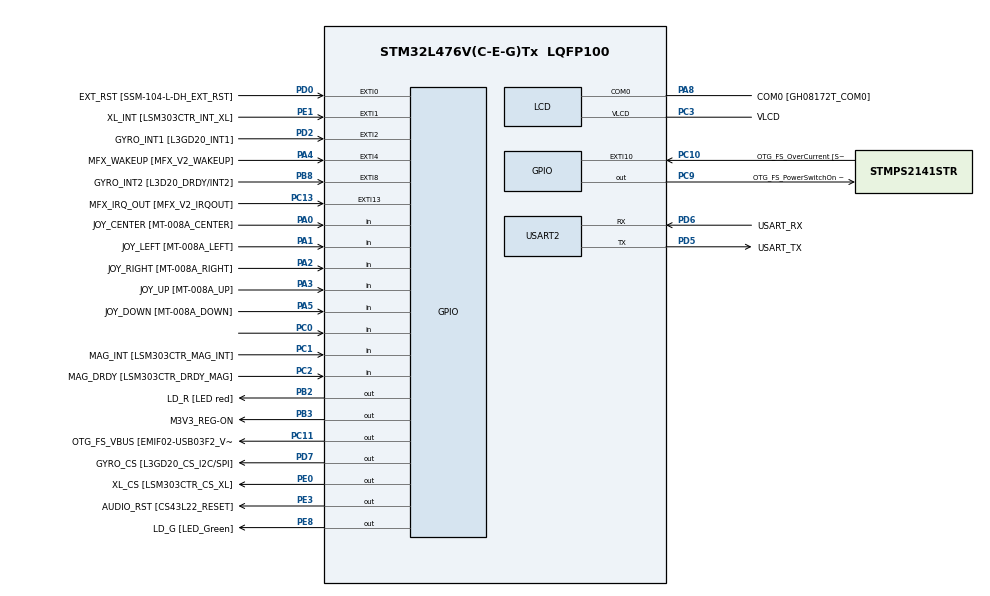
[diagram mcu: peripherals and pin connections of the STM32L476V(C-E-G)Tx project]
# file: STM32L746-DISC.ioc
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FREERTOS.Tasks01=defaultTask,0,128,StartDefaultTask,Default,NULL
Mcu.Family=STM32L4
Mcu.Name=STM32L476V(C-E-G)Tx
Mcu.Package=LQFP100
NVIC.PriorityGroup=NVIC_PRIORITYGROUP_4
PA0.GPIO_Label=JOY_CENTER [MT-008A_CENTER]
PA0.GPIO_Mode=GPIO_MODE_INPUT
PA0.GPIO_PuPd=GPIO_PULLDOWN
PA0.Signal=GPIO_Input
PA1.GPIO_Label=JOY_LEFT [MT-008A_LEFT]
PA1.GPIO_Mode=GPIO_MODE_INPUT
PA1.GPIO_PuPd=GPIO_PULLDOWN
PA1.Signal=GPIO_Input
PA10.GPIO_Label=COM2 [GH08172T_COM2]
PA10.GPIO_Mode=GPIO_MODE_AF_PP
PA10.GPIO_PuPd=GPIO_NOPULL
PA10.GPIO_Speed=GPIO_SPEED_FREQ_LOW
PA10.Signal=LCD_COM2
PA11.GPIO_Label=OTG_FS_DM [EMIF02-USB03F2_D-out]
PA11.GPIO_Mode=GPIO_MODE_AF_PP
PA11.GPIO_PuPd=GPIO_NOPULL
PA11.GPIO_Speed=GPIO_SPEED_FREQ_VERY_HIGH
PA11.Signal=USB_OTG_FS_DM
PA12.GPIO_Label=OTG_FS_DP [EMIF02-USB03F2_D+out]
PA12.GPIO_Mode=GPIO_MODE_AF_PP
PA12.GPIO_PuPd=GPIO_NOPULL
PA12.GPIO_Speed=GPIO_SPEED_FREQ_VERY_HIGH
PA12.Signal=USB_OTG_FS_DP
PA13\ (JTMS-SWDIO).GPIO_Label=SWDIO
PA13\ (JTMS-SWDIO).Signal=SYS_JTMS-SWDIO
PA14\ (JTCK-SWCLK).GPIO_Label=SWCLK
PA14\ (JTCK-SWCLK).Signal=SYS_JTCK-SWCLK
PA15\ (JTDI).GPIO_Label=SEG10 [GH08172T_SEG10]
PA15\ (JTDI).GPIO_Mode=GPIO_MODE_AF_PP
PA15\ (JTDI).GPIO_PuPd=GPIO_NOPULL
PA15\ (JTDI).GPIO_Speed=GPIO_SPEED_FREQ_LOW
PA15\ (JTDI).Signal=LCD_SEG17
PA2.GPIO_Label=JOY_RIGHT [MT-008A_RIGHT]
PA2.GPIO_Mode=GPIO_MODE_INPUT
PA2.GPIO_PuPd=GPIO_PULLDOWN
PA2.Signal=GPIO_Input
PA3.GPIO_Label=JOY_UP [MT-008A_UP]
PA3.GPIO_Mode=GPIO_MODE_INPUT
PA3.GPIO_PuPd=GPIO_PULLDOWN
PA3.Signal=GPIO_Input
PA4.GPIO_Label=MFX_WAKEUP [MFX_V2_WAKEUP]
PA4.GPIO_ModeDefaultEXTI=GPIO_MODE_EVT_RISING
PA4.GPIO_PuPd=GPIO_NOPULL
PA4.Signal=GPXTI4
PA5.GPIO_Label=JOY_DOWN [MT-008A_DOWN]
PA5.GPIO_Mode=GPIO_MODE_INPUT
PA5.GPIO_PuPd=GPIO_PULLDOWN
PA5.Signal=GPIO_Input
PA6.GPIO_Label=SEG23 [GH08172T_SEG23]
PA6.GPIO_Mode=GPIO_MODE_AF_PP
PA6.GPIO_PuPd=GPIO_NOPULL
PA6.GPIO_Speed=GPIO_SPEED_FREQ_LOW
PA6.Signal=LCD_SEG3
PA7.GPIO_Label=SEG0 [GH08172T_SEG0]
PA7.GPIO_Mode=GPIO_MODE_AF_PP
PA7.GPIO_PuPd=GPIO_NOPULL
PA7.GPIO_Speed=GPIO_SPEED_FREQ_LOW
PA7.Signal=LCD_SEG4
PA8.GPIO_Label=COM0 [GH08172T_COM0]
PA8.GPIO_Mode=GPIO_MODE_AF_PP
PA8.GPIO_PuPd=GPIO_NOPULL
PA8.GPIO_Speed=GPIO_SPEED_FREQ_LOW
PA8.Mode=Static
PA8.Signal=LCD_COM0
PA9.GPIO_Label=COM1 [GH08172T_COM1]
PA9.GPIO_Mode=GPIO_MODE_AF_PP
PA9.GPIO_PuPd=GPIO_NOPULL
PA9.GPIO_Speed=GPIO_SPEED_FREQ_LOW
PA9.Signal=LCD_COM1
PB0.GPIO_Label=SEG21 [GH08172T_SEG21]
PB0.GPIO_Mode=GPIO_MODE_AF_PP
PB0.GPIO_PuPd=GPIO_NOPULL
PB0.GPIO_Speed=GPIO_SPEED_FREQ_LOW
PB0.Signal=LCD_SEG5
PB1.GPIO_Label=SEG2 [GH08172T_SEG2]
PB1.GPIO_Mode=GPIO_MODE_AF_PP
PB1.GPIO_PuPd=GPIO_NOPULL
PB1.GPIO_Speed=GPIO_SPEED_FREQ_LOW
PB1.Signal=LCD_SEG6
PB10.GPIO_Label=MFX_I2C_SLC [MFX_V2_I2C_SCL]
PB10.GPIO_Mode=GPIO_MODE_AF_OD
PB10.GPIO_PuPdOD=GPIO_PULLUP
PB10.GPIO_Speed=GPIO_SPEED_FREQ_VERY_HIGH
PB10.Signal=I2C2_SCL
PB11.GPIO_Label=MFX_I2C_SDA [MFX_V2_I2C_SDA]
PB11.GPIO_Mode=GPIO_MODE_AF_OD
PB11.GPIO_PuPdOD=GPIO_PULLUP
PB11.GPIO_Speed=GPIO_SPEED_FREQ_VERY_HIGH
PB11.Signal=I2C2_SDA
PB12.GPIO_Label=SEG20 [GH08172T_SEG20]
PB12.GPIO_Mode=GPIO_MODE_AF_PP
PB12.GPIO_PuPd=GPIO_NOPULL
PB12.GPIO_Speed=GPIO_SPEED_FREQ_LOW
PB12.Signal=LCD_SEG12
PB13.GPIO_Label=SEG3 [GH08172T_SEG3]
PB13.GPIO_Mode=GPIO_MODE_AF_PP
PB13.GPIO_PuPd=GPIO_NOPULL
PB13.GPIO_Speed=GPIO_SPEED_FREQ_LOW
PB13.Signal=LCD_SEG13
PB14.GPIO_Label=SEG19 [GH08172T_SEG19]
PB14.GPIO_Mode=GPIO_MODE_AF_PP
PB14.GPIO_PuPd=GPIO_NOPULL
PB14.GPIO_Speed=GPIO_SPEED_FREQ_LOW
PB14.Signal=LCD_SEG14
PB15.GPIO_Label=SEG4 [GH08172T_SEG4]
PB15.GPIO_Mode=GPIO_MODE_AF_PP
PB15.GPIO_PuPd=GPIO_NOPULL
PB15.GPIO_Speed=GPIO_SPEED_FREQ_LOW
PB15.Signal=LCD_SEG15
PB2.GPIO_Label=LD_R [LED red]
PB2.GPIO_ModeDefaultOutputPP=GPIO_MODE_OUTPUT_PP
PB2.GPIO_PuPd=GPIO_PULLUP
PB2.GPIO_Speed=GPIO_SPEED_FREQ_VERY_HIGH
PB2.Signal=GPIO_Output
PB3\ (JTDO-TRACESWO).GPIO_Label=M3V3_REG-ON
PB3\ (JTDO-TRACESWO).GPIO_ModeDefaultOutputPP=GPIO_MODE_OUTPUT_PP
PB3\ (JTDO-TRACESWO).GPIO_PuPd=GPIO_NOPULL
PB3\ (JTDO-TRACESWO).GPIO_Speed=GPIO_SPEED_FREQ_LOW
PB3\ (JTDO-TRACESWO).Signal=GPIO_Output
PB4\ (NJTRST).GPIO_Label=SEG11 [GH08172T_SEG11]
PB4\ (NJTRST).GPIO_Mode=GPIO_MODE_AF_PP
PB4\ (NJTRST).GPIO_PuPd=GPIO_NOPULL
PB4\ (NJTRST).GPIO_Speed=GPIO_SPEED_FREQ_LOW
PB4\ (NJTRST).Signal=LCD_SEG8
PB5.GPIO_Label=SEG12 [GH08172T_SEG12]
PB5.GPIO_Mode=GPIO_MODE_AF_PP
PB5.GPIO_PuPd=GPIO_NOPULL
PB5.GPIO_Speed=GPIO_SPEED_FREQ_LOW
PB5.Signal=LCD_SEG9
PB6.GPIO_FM6=__NULL
PB6.GPIO_Label=I2C1_SCL [SSM-104-L-DH_SCL]
PB6.GPIO_Mode=GPIO_MODE_AF_OD
PB6.GPIO_PuPdOD=GPIO_PULLUP
PB6.GPIO_Speed=GPIO_SPEED_FREQ_VERY_HIGH
PB6.Signal=I2C1_SCL
PB7.GPIO_FM7=__NULL
PB7.GPIO_Label=I2C1_SDA [SSM-104-L-DH_SDA]
PB7.GPIO_Mode=GPIO_MODE_AF_OD
PB7.GPIO_PuPdOD=GPIO_PULLUP
PB7.GPIO_Speed=GPIO_SPEED_FREQ_VERY_HIGH
PB7.Signal=I2C1_SDA
PB8.GPIO_Label=GYRO_INT2 [L3D20_DRDY/INT2]
PB8.GPIO_ModeDefaultEXTI=GPIO_MODE_EVT_RISING
PB8.GPIO_PuPd=GPIO_NOPULL
PB8.Signal=GPXTI8
PB9.GPIO_FM9=__NULL
PB9.GPIO_Label=COM3 [GH08172T_COM3]
PB9.GPIO_Mode=GPIO_MODE_AF_PP
PB9.GPIO_PuPd=GPIO_NOPULL
PB9.GPIO_Speed=GPIO_SPEED_FREQ_LOW
PB9.Signal=LCD_COM3
PC0.Signal=GPIO_Input
PC1.GPIO_Label=MAG_INT [LSM303CTR_MAG_INT]
PC1.GPIO_Mode=GPIO_MODE_INPUT
PC1.GPIO_PuPd=GPIO_NOPULL
PC1.Signal=GPIO_Input
PC10.GPIO_Label=OTG_FS_OverCurrent [STMPS2141STR_FAULT]
PC10.GPIO_ModeDefaultEXTI=GPIO_MODE_EVT_RISING
PC10.GPIO_PuPd=GPIO_NOPULL
PC10.Signal=GPXTI10
PC11.GPIO_Label=OTG_FS_VBUS [EMIF02-USB03F2_Vbus]
PC11.GPIO_ModeDefaultOutputPP=GPIO_MODE_OUTPUT_PP
PC11.GPIO_PuPd=GPIO_NOPULL
PC11.GPIO_Speed=GPIO_SPEED_FREQ_LOW
PC11.Signal=GPIO_Output
PC13.GPIO_Label=MFX_IRQ_OUT [MFX_V2_IRQOUT]
PC13.GPIO_ModeDefaultEXTI=GPIO_MODE_EVT_RISING
PC13.GPIO_PuPd=GPIO_NOPULL
PC13.Signal=GPXTI13
PC14-OSC32_IN\ (PC14).Signal=RCC_OSC32_IN
PC15-OSC32_OUT\ (PC15).Signal=RCC_OSC32_OUT
PC2.GPIO_Label=MAG_DRDY [LSM303CTR_DRDY_MAG]
PC2.GPIO_Mode=GPIO_MODE_INPUT
PC2.GPIO_PuPd=GPIO_NOPULL
PC2.Signal=GPIO_Input
PC3.GPIO_Label=VLCD
PC3.GPIO_Mode=GPIO_MODE_AF_PP
PC3.GPIO_PuPd=GPIO_NOPULL
PC3.GPIO_Speed=GPIO_SPEED_FREQ_LOW
PC3.Mode=Static
PC3.Signal=LCD_VLCD
PC4.GPIO_Label=SEG22 [GH08172T_SEG22]
PC4.GPIO_Mode=GPIO_MODE_AF_PP
PC4.GPIO_PuPd=GPIO_NOPULL
PC4.GPIO_Speed=GPIO_SPEED_FREQ_LOW
PC4.Signal=LCD_SEG22
PC5.GPIO_Label=SEG1 [GH08172T_SEG1]
PC5.GPIO_Mode=GPIO_MODE_AF_PP
PC5.GPIO_PuPd=GPIO_NOPULL
PC5.GPIO_Speed=GPIO_SPEED_FREQ_LOW
PC5.Signal=LCD_SEG23
PC6.GPIO_Label=SEG14 [GH08172T_SEG14]
PC6.GPIO_Mode=GPIO_MODE_AF_PP
PC6.GPIO_PuPd=GPIO_NOPULL
PC6.GPIO_Speed=GPIO_SPEED_FREQ_LOW
PC6.Signal=LCD_SEG24
PC7.GPIO_Label=SEG9 [GH08172T_SEG9]
PC7.GPIO_Mode=GPIO_MODE_AF_PP
PC7.GPIO_PuPd=GPIO_NOPULL
PC7.GPIO_Speed=GPIO_SPEED_FREQ_LOW
PC7.Signal=LCD_SEG25
PC8.GPIO_Label=SEG13 [GH08172T_SEG13]
PC8.GPIO_Mode=GPIO_MODE_AF_PP
PC8.GPIO_PuPd=GPIO_NOPULL
PC8.GPIO_Speed=GPIO_SPEED_FREQ_LOW
PC8.Signal=LCD_SEG26
PC9.GPIO_Label=OTG_FS_PowerSwitchOn [STMPS2141STR_EN]
PC9.GPIO_ModeDefaultOutputPP=GPIO_MODE_OUTPUT_PP
PC9.GPIO_PuPd=GPIO_NOPULL
PC9.GPIO_Speed=GPIO_SPEED_FREQ_LOW
PC9.PinState=GPIO_PIN_SET
PC9.Signal=GPIO_Output
PD0.GPIO_Label=EXT_RST [SSM-104-L-DH_EXT_RST]
PD0.GPIO_ModeDefaultEXTI=GPIO_MODE_EVT_RISING
PD0.GPIO_PuPd=GPIO_NOPULL
PD0.Signal=GPXTI0
PD1.GPIO_Label=MEMS_SCK [L3GD20_SCL/SPC]
PD1.GPIO_Mode=GPIO_MODE_AF_PP
PD1.GPIO_PuPd=GPIO_NOPULL
PD1.GPIO_Speed=GPIO_SPEED_FREQ_VERY_HIGH
PD1.Signal=SPI2_SCK
PD10.GPIO_Label=SEG17 [GH08172T_SEG17]
PD10.GPIO_Mode=GPIO_MODE_AF_PP
PD10.GPIO_PuPd=GPIO_NOPULL
PD10.GPIO_Speed=GPIO_SPEED_FREQ_LOW
PD10.Signal=LCD_SEG30
PD11.GPIO_Label=SEG6 [GH08172T_SEG6]
PD11.GPIO_Mode=GPIO_MODE_AF_PP
PD11.GPIO_PuPd=GPIO_NOPULL
PD11.GPIO_Speed=GPIO_SPEED_FREQ_LOW
PD11.Signal=LCD_SEG31
PD12.GPIO_Label=SEG16 [GH08172T_SEG16]
PD12.GPIO_Mode=GPIO_MODE_AF_PP
PD12.GPIO_PuPd=GPIO_NOPULL
PD12.GPIO_Speed=GPIO_SPEED_FREQ_LOW
PD12.Signal=LCD_SEG32
PD13.GPIO_Label=SEG7 [GH08172T_SEG7]
PD13.GPIO_Mode=GPIO_MODE_AF_PP
PD13.GPIO_PuPd=GPIO_NOPULL
PD13.GPIO_Speed=GPIO_SPEED_FREQ_LOW
PD13.Signal=LCD_SEG33
PD14.GPIO_Label=SEG15 [GH08172T_SEG15]
PD14.GPIO_Mode=GPIO_MODE_AF_PP
PD14.GPIO_PuPd=GPIO_NOPULL
PD14.GPIO_Speed=GPIO_SPEED_FREQ_LOW
PD14.Signal=LCD_SEG34
PD15.GPIO_Label=SEG8 [GH08172T_SEG8]
PD15.GPIO_Mode=GPIO_MODE_AF_PP
PD15.GPIO_PuPd=GPIO_NOPULL
PD15.GPIO_Speed=GPIO_SPEED_FREQ_LOW
PD15.Signal=LCD_SEG35
PD2.GPIO_Label=GYRO_INT1 [L3GD20_INT1]
PD2.GPIO_ModeDefaultEXTI=GPIO_MODE_EVT_RISING
PD2.GPIO_PuPd=GPIO_NOPULL
PD2.Signal=GPXTI2
PD3.GPIO_Label=MEMS_MISO [L3GD20_SA0/SDO]
PD3.GPIO_Mode=GPIO_MODE_AF_PP
PD3.GPIO_PuPd=GPIO_NOPULL
PD3.GPIO_Speed=GPIO_SPEED_FREQ_VERY_HIGH
PD3.Signal=SPI2_MISO
PD4.GPIO_Label=MEMS_MOSI [L3GD20_SDA/SDI/SDO]
PD4.GPIO_Mode=GPIO_MODE_AF_PP
PD4.GPIO_PuPd=GPIO_NOPULL
PD4.GPIO_Speed=GPIO_SPEED_FREQ_VERY_HIGH
PD4.Signal=SPI2_MOSI
PD5.GPIO_Label=USART_TX
PD5.GPIO_Mode=GPIO_MODE_AF_PP
PD5.GPIO_PuPd=GPIO_PULLUP
PD5.GPIO_Speed=GPIO_SPEED_FREQ_VERY_HIGH
PD5.Mode=Asynchronous
PD5.Signal=USART2_TX
PD6.GPIO_Label=USART_RX
PD6.GPIO_Mode=GPIO_MODE_AF_PP
PD6.GPIO_PuPd=GPIO_PULLUP
PD6.GPIO_Speed=GPIO_SPEED_FREQ_VERY_HIGH
PD6.Mode=Asynchronous
PD6.Signal=USART2_RX
PD7.GPIO_Label=GYRO_CS [L3GD20_CS_I2C/SPI]
PD7.GPIO_ModeDefaultOutputPP=GPIO_MODE_OUTPUT_PP
PD7.GPIO_PuPd=GPIO_NOPULL
PD7.GPIO_Speed=GPIO_SPEED_FREQ_VERY_HIGH
PD7.Signal=GPIO_Output
PD8.GPIO_Label=SEG18 [GH08172T_SEG18]
PD8.GPIO_Mode=GPIO_MODE_AF_PP
PD8.GPIO_PuPd=GPIO_NOPULL
PD8.GPIO_Speed=GPIO_SPEED_FREQ_LOW
PD8.Signal=LCD_SEG28
PD9.GPIO_Label=SEG5 [GH08172T_SEG5]
PD9.GPIO_Mode=GPIO_MODE_AF_PP
PD9.GPIO_PuPd=GPIO_NOPULL
PD9.GPIO_Speed=GPIO_SPEED_FREQ_LOW
PD9.Signal=LCD_SEG29
PE0.GPIO_Label=XL_CS [LSM303CTR_CS_XL]
PE0.GPIO_ModeDefaultOutputPP=GPIO_MODE_OUTPUT_PP
PE0.GPIO_PuPd=GPIO_NOPULL
PE0.GPIO_Speed=GPIO_SPEED_FREQ_LOW
PE0.Signal=GPIO_Output
PE1.GPIO_Label=XL_INT [LSM303CTR_INT_XL]
PE1.GPIO_ModeDefaultEXTI=GPIO_MODE_EVT_RISING
PE1.GPIO_PuPd=GPIO_NOPULL
PE1.Signal=GPXTI1
PE10.GPIO_Label=QSPI_CLK [N25Q128A13EF840E_C]
PE10.GPIO_Mode=GPIO_MODE_AF_PP
PE10.GPIO_PuPd=GPIO_NOPULL
PE10.GPIO_Speed=GPIO_SPEED_FREQ_VERY_HIGH
PE10.Signal=QUADSPI_CLK
PE11.GPIO_Label=QSPI_CS [N25Q128A13EF840E_S\#]
PE11.GPIO_Mode=GPIO_MODE_AF_PP
PE11.GPIO_PuPd=GPIO_NOPULL
PE11.GPIO_Speed=GPIO_SPEED_FREQ_VERY_HIGH
PE11.Signal=QUADSPI_NCS
PE12.GPIO_Label=QSPI_D0 [N25Q128A13EF840E_DQ0]
PE12.GPIO_Mode=GPIO_MODE_AF_PP
PE12.GPIO_PuPd=GPIO_NOPULL
PE12.GPIO_Speed=GPIO_SPEED_FREQ_VERY_HIGH
PE12.Signal=QUADSPI_BK1_IO0
PE13.GPIO_Label=QSPI_D1 [N25Q128A13EF840E_DQ1]
PE13.GPIO_Mode=GPIO_MODE_AF_PP
PE13.GPIO_PuPd=GPIO_NOPULL
PE13.GPIO_Speed=GPIO_SPEED_FREQ_VERY_HIGH
PE13.Signal=QUADSPI_BK1_IO1
PE14.GPIO_Label=QSPI_D2 [N25Q128A13EF840E_DQ2]
PE14.GPIO_Mode=GPIO_MODE_AF_PP
PE14.GPIO_PuPd=GPIO_NOPULL
PE14.GPIO_Speed=GPIO_SPEED_FREQ_VERY_HIGH
PE14.Signal=QUADSPI_BK1_IO2
PE15.GPIO_Label=QSPI_D3 [N25Q128A13EF840E_DQ3]
PE15.GPIO_Mode=GPIO_MODE_AF_PP
PE15.GPIO_PuPd=GPIO_NOPULL
PE15.GPIO_Speed=GPIO_SPEED_FREQ_VERY_HIGH
PE15.Signal=QUADSPI_BK1_IO3
PE2.GPIO_Label=SAI1_MCK [CS43L22_MCLK]
PE2.GPIO_Mode=GPIO_MODE_AF_PP
PE2.GPIO_PuPd=GPIO_NOPULL
PE2.GPIO_Speed=GPIO_SPEED_FREQ_VERY_HIGH
PE2.Signal=SAI1_MCLK_A
PE3.GPIO_Label=AUDIO_RST [CS43L22_RESET]
PE3.GPIO_ModeDefaultOutputPP=GPIO_MODE_OUTPUT_PP
PE3.GPIO_PuPd=GPIO_NOPULL
PE3.GPIO_Speed=GPIO_SPEED_FREQ_HIGH
PE3.Signal=GPIO_Output
PE4.GPIO_Label=SAI1_FS [CS43L22_LRCK]
PE4.GPIO_Mode=GPIO_MODE_AF_PP
PE4.GPIO_PuPd=GPIO_NOPULL
PE4.GPIO_Speed=GPIO_SPEED_FREQ_VERY_HIGH
PE4.Signal=SAI1_FS_A
PE5.GPIO_Label=SAI1_SCK [CS43L22_SCLK]
PE5.GPIO_Mode=GPIO_MODE_AF_PP
PE5.GPIO_PuPd=GPIO_NOPULL
PE5.GPIO_Speed=GPIO_SPEED_FREQ_VERY_HIGH
PE5.Signal=SAI1_SCK_A
PE6.GPIO_Label=SAI1_SD [CS43L22_SDIN]
PE6.GPIO_Mode=GPIO_MODE_AF_PP
PE6.GPIO_PuPd=GPIO_NOPULL
PE6.GPIO_Speed=GPIO_SPEED_FREQ_VERY_HIGH
PE6.Signal=SAI1_SD_A
PE7.GPIO_Label=AUDIO_DIN [MP34DT01_DOUT]
PE7.GPIO_Mode=GPIO_MODE_AF_PP
PE7.GPIO_PuPd=GPIO_NOPULL
PE7.GPIO_Speed=GPIO_SPEED_FREQ_VERY_HIGH
PE7.Signal=SAI1_SD_B
PE8.GPIO_Label=LD_G [LED_Green]
PE8.GPIO_ModeDefaultOutputPP=GPIO_MODE_OUTPUT_PP
PE8.GPIO_PuPd=GPIO_PULLUP
PE8.GPIO_Speed=GPIO_SPEED_FREQ_VERY_HIGH
PE8.Signal=GPIO_Output
PE9.GPIO_Label=AUDIO_CLK [MP34DT01_CLK]
PE9.GPIO_Mode=GPIO_MODE_AF_PP
PE9.GPIO_PuPd=GPIO_NOPULL
PE9.GPIO_Speed=GPIO_SPEED_FREQ_LOW
PE9.Signal=SAI1_FS_B
PH0-OSC_IN\ (PH0).Signal=RCC_OSC_IN
PH1-OSC_OUT\ (PH1).Signal=RCC_OSC_OUT
ProjectManager.HeapSize=0x200
ProjectManager.StackSize=0x400
ProjectManager.TargetToolchain=SW4STM32
RCC.CortexFreq_Value=4000000
RCC.HSE_VALUE=8000000
RCC.HSI_VALUE=16000000
RCC.LSE_VALUE=32768
RCC.MSI_VALUE=4000000
RCC.PREFETCH_ENABLE=1
RCC.VCOOutputFreq_Value=32000000
USART2.VirtualMode-Asynchronous=VM_ASYNC
VP_FREERTOS_VS_ENABLE.Mode=Enabled
board=STM32L476G-DISCO

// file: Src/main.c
/**
  ******************************************************************************
  * File Name          : main.c
  * Description        : Main program body
  ******************************************************************************
  * This notice applies to any and all portions of this file
  * that are not between comment pairs USER CODE BEGIN and
  * USER CODE END. Other portions of this file, whether
  * inserted by the user or by software development tools
  * are owned by their respective copyright owners.
  *
  * Copyright (c) 2017 STMicroelectronics International N.V.
  * All rights reserved.
  *
  * Redistribution and use in source and binary forms, with or without
  * modification, are permitted, provided that the following conditions are met:
  *
  * 1. Redistribution of source code must retain the above copyright notice,
  *    this list of conditions and the following disclaimer.
  * 2. Redistributions in binary form must reproduce the above copyright notice,
  *    this list of conditions and the following disclaimer in the documentation
  *    and/or other materials provided with the distribution.
  * 3. Neither the name of STMicroelectronics nor the names of other
  *    contributors to this software may be used to endorse or promote products
  *    derived from this software without specific written permission.
  * 4. This software, including modifications and/or derivative works of this
  *    software, must execute solely and exclusively on microcontroller or
  *    microprocessor devices manufactured by or for STMicroelectronics.
  * 5. Redistribution and use of this software other than as permitted under
  *    this license is void and will automatically terminate your rights under
  *    this license.
  *
  * THIS SOFTWARE IS PROVIDED BY STMICROELECTRONICS AND CONTRIBUTORS "AS IS"
  * AND ANY EXPRESS, IMPLIED OR STATUTORY WARRANTIES, INCLUDING, BUT NOT
  * LIMITED TO, THE IMPLIED WARRANTIES OF MERCHANTABILITY, FITNESS FOR A
  * PARTICULAR PURPOSE AND NON-INFRINGEMENT OF THIRD PARTY INTELLECTUAL PROPERTY
  * RIGHTS ARE DISCLAIMED TO THE FULLEST EXTENT PERMITTED BY LAW. IN NO EVENT
  * SHALL STMICROELECTRONICS OR CONTRIBUTORS BE LIABLE FOR ANY DIRECT, INDIRECT,
  * INCIDENTAL, SPECIAL, EXEMPLARY, OR CONSEQUENTIAL DAMAGES (INCLUDING, BUT NOT
  * LIMITED TO, PROCUREMENT OF SUBSTITUTE GOODS OR SERVICES; LOSS OF USE, DATA,
  * OR PROFITS; OR BUSINESS INTERRUPTION) HOWEVER CAUSED AND ON ANY THEORY OF
  * LIABILITY, WHETHER IN CONTRACT, STRICT LIABILITY, OR TORT (INCLUDING
  * NEGLIGENCE OR OTHERWISE) ARISING IN ANY WAY OUT OF THE USE OF THIS SOFTWARE,
  * EVEN IF ADVISED OF THE POSSIBILITY OF SUCH DAMAGE.
  *
  ******************************************************************************
  */

#include "main.h"
#include "stm32l4xx_hal.h"
#include "cmsis_os.h"
#include "usart.h"
#include "usb_device.h"
#include "gpio.h"

/* USER CODE BEGIN PV */
/* Private variables ---------------------------------------------------------*/

/* USER CODE END PV */

void SystemClock_Config(void);
void MX_FREERTOS_Init(void);

/* USER CODE BEGIN PFP */
/* Private function prototypes -----------------------------------------------*/

/* USER CODE END PFP */

int main(void)
{

  /* MCU Configuration----------------------------------------------------------*/

  /* Reset of all peripherals, Initializes the Flash interface and the Systick. */
  HAL_Init();

  /* Configure the system clock */
  SystemClock_Config();

  /* Initialize all configured peripherals */
  MX_GPIO_Init();
  MX_USART2_UART_Init();

  /* USER CODE BEGIN 2 */
#ifdef ENABLE_LCD
  BSP_LCD_GLASS_Init();
#endif
  TRACE("FreeRTOS ready to start.....\n");
  /* USER CODE END 2 */

  /* Call init function for freertos objects (in freertos.c) */
  MX_FREERTOS_Init();

  /* Start scheduler */
  osKernelStart();

  /* We should never get here as control is now taken by the scheduler */

  /* Infinite loop */
  while (1)
  {

  }

}

/** System Clock Configuration
*/
void SystemClock_Config(void)
{

  RCC_OscInitTypeDef RCC_OscInitStruct;
  RCC_ClkInitTypeDef RCC_ClkInitStruct;
  RCC_PeriphCLKInitTypeDef PeriphClkInit;

    /**Initializes the CPU, AHB and APB busses clocks
    */
  RCC_OscInitStruct.OscillatorType = RCC_OSCILLATORTYPE_MSI;
  RCC_OscInitStruct.MSIState = RCC_MSI_ON;
  RCC_OscInitStruct.MSICalibrationValue = 0;
  RCC_OscInitStruct.MSIClockRange = RCC_MSIRANGE_6;
  RCC_OscInitStruct.PLL.PLLState = RCC_PLL_ON;
  RCC_OscInitStruct.PLL.PLLSource = RCC_PLLSOURCE_MSI;
  RCC_OscInitStruct.PLL.PLLM = 1;
  RCC_OscInitStruct.PLL.PLLN = 40;
  RCC_OscInitStruct.PLL.PLLP = RCC_PLLP_DIV7;
  RCC_OscInitStruct.PLL.PLLQ = RCC_PLLQ_DIV2;
  RCC_OscInitStruct.PLL.PLLR = RCC_PLLR_DIV2;
  if (HAL_RCC_OscConfig(&RCC_OscInitStruct) != HAL_OK)
  {
    _Error_Handler(__FILE__, __LINE__);
  }

    /**Initializes the CPU, AHB and APB busses clocks
    */
  RCC_ClkInitStruct.ClockType = RCC_CLOCKTYPE_HCLK|RCC_CLOCKTYPE_SYSCLK
                              |RCC_CLOCKTYPE_PCLK1|RCC_CLOCKTYPE_PCLK2;
  RCC_ClkInitStruct.SYSCLKSource = RCC_SYSCLKSOURCE_PLLCLK;
  RCC_ClkInitStruct.AHBCLKDivider = RCC_SYSCLK_DIV1;
  RCC_ClkInitStruct.APB1CLKDivider = RCC_HCLK_DIV1;
  RCC_ClkInitStruct.APB2CLKDivider = RCC_HCLK_DIV1;

  if (HAL_RCC_ClockConfig(&RCC_ClkInitStruct, FLASH_LATENCY_3) != HAL_OK)
  {
    _Error_Handler(__FILE__, __LINE__);
  }

  PeriphClkInit.PeriphClockSelection = RCC_PERIPHCLK_USART2|RCC_PERIPHCLK_USB;
  PeriphClkInit.Usart2ClockSelection = RCC_USART2CLKSOURCE_PCLK1;
  PeriphClkInit.UsbClockSelection = RCC_USBCLKSOURCE_PLLSAI1;
  PeriphClkInit.PLLSAI1.PLLSAI1Source = RCC_PLLSOURCE_MSI;
  PeriphClkInit.PLLSAI1.PLLSAI1M = 1;
  PeriphClkInit.PLLSAI1.PLLSAI1N = 24;
  PeriphClkInit.PLLSAI1.PLLSAI1P = RCC_PLLP_DIV7;
  PeriphClkInit.PLLSAI1.PLLSAI1Q = RCC_PLLQ_DIV2;
  PeriphClkInit.PLLSAI1.PLLSAI1R = RCC_PLLR_DIV2;
  PeriphClkInit.PLLSAI1.PLLSAI1ClockOut = RCC_PLLSAI1_48M2CLK;
  if (HAL_RCCEx_PeriphCLKConfig(&PeriphClkInit) != HAL_OK)
  {
    _Error_Handler(__FILE__, __LINE__);
  }

    /**Configure the main internal regulator output voltage
    */
  if (HAL_PWREx_ControlVoltageScaling(PWR_REGULATOR_VOLTAGE_SCALE1) != HAL_OK)
  {
    _Error_Handler(__FILE__, __LINE__);
  }

    /**Configure the Systick interrupt time
    */
  HAL_SYSTICK_Config(HAL_RCC_GetHCLKFreq()/1000);

    /**Configure the Systick
    */
  HAL_SYSTICK_CLKSourceConfig(SYSTICK_CLKSOURCE_HCLK);

  /* SysTick_IRQn interrupt configuration */
  HAL_NVIC_SetPriority(SysTick_IRQn, 15, 0);
}

void _Error_Handler(char * file, int line)
{
  while(1)
  {
  }
}

/************************ (C) COPYRIGHT STMicroelectronics *****END OF FILE****/

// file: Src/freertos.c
/**
  ******************************************************************************
  * File Name          : freertos.c
  * Description        : Code for freertos applications
  ******************************************************************************
  * This notice applies to any and all portions of this file
  * that are not between comment pairs USER CODE BEGIN and
  * USER CODE END. Other portions of this file, whether
  * inserted by the user or by software development tools
  * are owned by their respective copyright owners.
  *
  * Copyright (c) 2017 STMicroelectronics International N.V.
  * All rights reserved.
  *
  * Redistribution and use in source and binary forms, with or without
  * modification, are permitted, provided that the following conditions are met:
  *
  * 1. Redistribution of source code must retain the above copyright notice,
  *    this list of conditions and the following disclaimer.
  * 2. Redistributions in binary form must reproduce the above copyright notice,
  *    this list of conditions and the following disclaimer in the documentation
  *    and/or other materials provided with the distribution.
  * 3. Neither the name of STMicroelectronics nor the names of other
  *    contributors to this software may be used to endorse or promote products
  *    derived from this software without specific written permission.
  * 4. This software, including modifications and/or derivative works of this
  *    software, must execute solely and exclusively on microcontroller or
  *    microprocessor devices manufactured by or for STMicroelectronics.
  * 5. Redistribution and use of this software other than as permitted under
  *    this license is void and will automatically terminate your rights under
  *    this license.
  *
  * THIS SOFTWARE IS PROVIDED BY STMICROELECTRONICS AND CONTRIBUTORS "AS IS"
  * AND ANY EXPRESS, IMPLIED OR STATUTORY WARRANTIES, INCLUDING, BUT NOT
  * LIMITED TO, THE IMPLIED WARRANTIES OF MERCHANTABILITY, FITNESS FOR A
  * PARTICULAR PURPOSE AND NON-INFRINGEMENT OF THIRD PARTY INTELLECTUAL PROPERTY
  * RIGHTS ARE DISCLAIMED TO THE FULLEST EXTENT PERMITTED BY LAW. IN NO EVENT
  * SHALL STMICROELECTRONICS OR CONTRIBUTORS BE LIABLE FOR ANY DIRECT, INDIRECT,
  * INCIDENTAL, SPECIAL, EXEMPLARY, OR CONSEQUENTIAL DAMAGES (INCLUDING, BUT NOT
  * LIMITED TO, PROCUREMENT OF SUBSTITUTE GOODS OR SERVICES; LOSS OF USE, DATA,
  * OR PROFITS; OR BUSINESS INTERRUPTION) HOWEVER CAUSED AND ON ANY THEORY OF
  * LIABILITY, WHETHER IN CONTRACT, STRICT LIABILITY, OR TORT (INCLUDING
  * NEGLIGENCE OR OTHERWISE) ARISING IN ANY WAY OUT OF THE USE OF THIS SOFTWARE,
  * EVEN IF ADVISED OF THE POSSIBILITY OF SUCH DAMAGE.
  *
  ******************************************************************************
  */

#include "FreeRTOS.h"
#include "task.h"
#include "cmsis_os.h"

/* USER CODE BEGIN Includes */
#include "user_tasks.h"

/* USER CODE END Includes */

osThreadId defaultTaskHandle;

/* USER CODE BEGIN Variables */
#ifdef ENABLE_LCD
osThreadId lcdTaskHandle;
#endif

/* USER CODE END Variables */

void StartDefaultTask(void const * argument);

extern void MX_USB_DEVICE_Init(void);
void MX_FREERTOS_Init(void); /* (MISRA C 2004 rule 8.1) */

/* Hook prototypes */

/* Init FreeRTOS */

void MX_FREERTOS_Init(void) {

  /* Create the thread(s) */
  /* definition and creation of defaultTask */
  osThreadDef(defaultTask, StartDefaultTask, osPriorityNormal, 0, 128);
  defaultTaskHandle = osThreadCreate(osThread(defaultTask), NULL);

  /* USER CODE BEGIN RTOS_THREADS */
  /* add threads, ... */
#ifdef ENABLE_LCD
  // LCD task
  osThreadDef(LcdTask, StartLcdTask, osPriorityNormal, 0, 128);
  lcdTaskHandle = osThreadCreate(osThread(LcdTask), NULL);
#endif
  /* USER CODE END RTOS_THREADS */

}

/* StartDefaultTask function */
void StartDefaultTask(void const * argument)
{
  /* init code for USB_DEVICE */
  MX_USB_DEVICE_Init();

  for(;;)
  {
    osDelay(1);
  }
}

/************************ (C) COPYRIGHT STMicroelectronics *****END OF FILE****/
